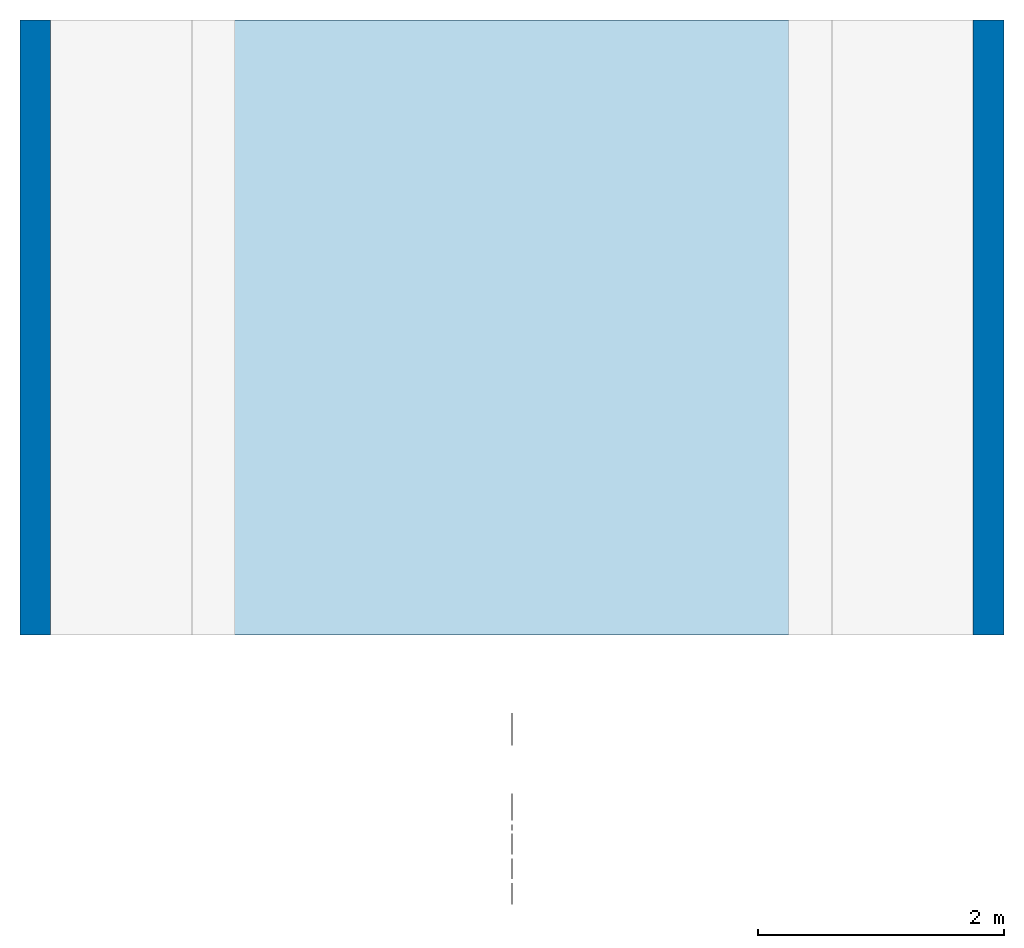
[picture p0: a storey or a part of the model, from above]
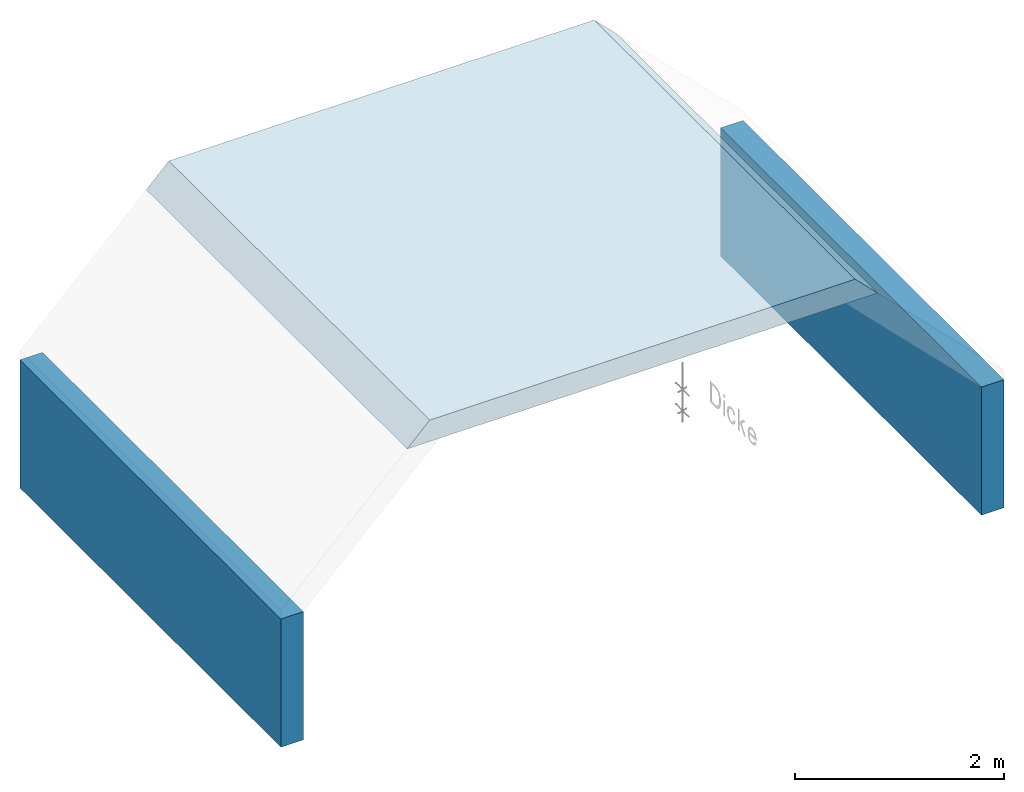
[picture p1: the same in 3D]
Properties of the parts of a building model (IFC4)

# File
Description: no view
File name: ÖBV_OEBV_Richtlinie_Sargdeckel.ifc
Time: 2024-03-13T09:47:40
Author: Oesterreichische Bautechnik Vereinigung
Organization: OEBV
Written by: ODA SDAI 24.5
Authorization: OEBV

# IfcSite, Liegenschaft
RefLatitude: 48, 8, 10, 320000; RefLongitude: 11, 41, 19, 320000

# IfcBuildingStorey, Geschoss 01
In: Gebäude
Elevation: 0 m

# IfcBuildingElementProxy (4)
In: Geschoss 01
Name | Allright_Bauteil_ID
macro | 0017Mak0000000050
 | 0017Mak0000000074
macro | 0017Mak0000000571
 | 0017Mak0000000574

# IfcElementAssembly (6)
In: Geschoss 01
Name | Allright_Bauteil_ID
SpatialDim_Group | 0017Elg0000000051
SpatialDim_Group | 0017Elg0000000063
SpatialDim_Group | 0017Elg0000000572
SpatialDim_Group | 0017Elg0000000575
2 x WA_01

# IfcSlab (2)
In: Geschoss 01
Name | Allright_Bauteil_ID
 | 0017ErE0000010730
 | 0017ErE0000010731

# IfcWall (2)
In: Geschoss 01
Description: Außenwand; Material: C20/25
Name | Allright_Bauteil_ID
WA_01 | 0017Wa 0000013170
WA_01 | 0017Wa 0000013178
